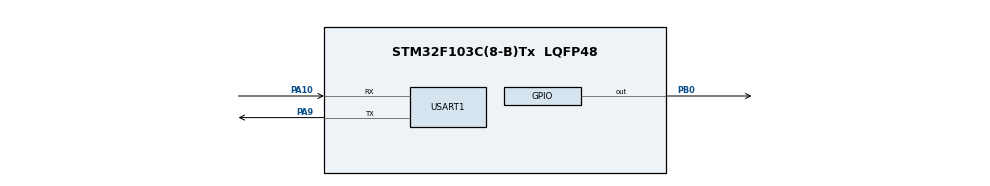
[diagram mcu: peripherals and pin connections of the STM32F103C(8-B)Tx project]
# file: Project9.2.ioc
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Mcu.Family=STM32F1
Mcu.Name=STM32F103C(8-B)Tx
Mcu.Package=LQFP48
NVIC.PriorityGroup=NVIC_PRIORITYGROUP_4
PA10.Mode=Asynchronous
PA10.Signal=USART1_RX
PA13.Mode=Serial_Wire
PA13.Signal=SYS_JTMS-SWDIO
PA14.Mode=Serial_Wire
PA14.Signal=SYS_JTCK-SWCLK
PA9.Mode=Asynchronous
PA9.Signal=USART1_TX
PB0.Signal=GPIO_Output
PD0-OSC_IN.Mode=HSE-External-Oscillator
PD0-OSC_IN.Signal=RCC_OSC_IN
PD1-OSC_OUT.Mode=HSE-External-Oscillator
PD1-OSC_OUT.Signal=RCC_OSC_OUT
ProjectManager.HeapSize=0x200
ProjectManager.StackSize=0x400
ProjectManager.TargetToolchain=MDK-ARM V5.32
RCC.AHBFreq_Value=72000000
RCC.APB1CLKDivider=RCC_HCLK_DIV2
RCC.APB1Freq_Value=36000000
RCC.APB1TimFreq_Value=72000000
RCC.APB2Freq_Value=72000000
RCC.APB2TimFreq_Value=72000000
RCC.HCLKFreq_Value=72000000
RCC.PLLMUL=RCC_PLL_MUL9
RCC.PLLSourceVirtual=RCC_PLLSOURCE_HSE
RCC.SYSCLKFreq_VALUE=72000000
RCC.SYSCLKSource=RCC_SYSCLKSOURCE_PLLCLK
RCC.USBFreq_Value=72000000
USART1.VirtualMode=VM_ASYNC
board=custom

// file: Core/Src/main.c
/* USER CODE BEGIN Header */
/**
  ******************************************************************************
  * @file           : main.c
  * @brief          : Main program body
  ******************************************************************************
  * @attention
  *
  * Copyright (c) 2026 STMicroelectronics.
  * All rights reserved.
  *
  * This software is licensed under terms that can be found in the LICENSE file
  * in the root directory of this software component.
  * If no LICENSE file comes with this software, it is provided AS-IS.
  *
  ******************************************************************************
  */
/* USER CODE END Header */
#include "main.h"

/* USER CODE BEGIN Includes */
#include <string.h>
/* USER CODE END Includes */

/* USER CODE BEGIN PD */
#define RX_BUF_SIZE 32
/* USER CODE END PD */

UART_HandleTypeDef huart1;

/* USER CODE BEGIN PV */
char rx_buf[RX_BUF_SIZE];
uint8_t rx_idx = 0;
uint8_t rx_char;
/* USER CODE END PV */

void SystemClock_Config(void);
static void MX_GPIO_Init(void);
static void MX_USART1_UART_Init(void);
/* USER CODE BEGIN PFP */
static void uart_print(const char *s);
static void process_command(char *cmd);
/* USER CODE END PFP */

int main(void)
{

  /* MCU Configuration--------------------------------------------------------*/

  /* Reset of all peripherals, Initializes the Flash interface and the Systick. */
  HAL_Init();

  /* Configure the system clock */
  SystemClock_Config();

  /* Initialize all configured peripherals */
  MX_GPIO_Init();
  MX_USART1_UART_Init();
  /* USER CODE BEGIN 2 */
  /* 3 blinks = firmware is running (PC13 is active-low) */
  for (int i = 0; i < 6; i++)
  {
    HAL_GPIO_TogglePin(GPIOC, GPIO_PIN_13);
    HAL_Delay(200);
  }
  HAL_GPIO_WritePin(GPIOC, GPIO_PIN_13, GPIO_PIN_SET); /* LED off */

  uart_print("\r\nSTM32 LED Command Interface\r\n");
  uart_print("Commands: LED ON | LED OFF | LED TOGGLE\r\n");
  uart_print("> ");
  /* USER CODE END 2 */

  /* Infinite loop */
  while (1)
  {

    /* USER CODE BEGIN 3 */
    if (HAL_UART_Receive(&huart1, &rx_char, 1, HAL_MAX_DELAY) == HAL_OK)
    {
      if (rx_char == '\r' || rx_char == '\n')      /* Enter pressed */
      {
        uart_print("\r\n");
        rx_buf[rx_idx] = '\0';
        process_command(rx_buf);
        rx_idx = 0;
        uart_print("> ");
      }
      else if (rx_char == 0x08 || rx_char == 0x7F) /* Backspace */
      {
        if (rx_idx > 0)
        {
          rx_idx--;
          uart_print("\b \b");
        }
      }
      else if (rx_idx < RX_BUF_SIZE - 1)
      {
        rx_buf[rx_idx++] = rx_char;
        HAL_UART_Transmit(&huart1, &rx_char, 1, HAL_MAX_DELAY); /* echo typed char */
      }
    }
  }
  /* USER CODE END 3 */
}

void SystemClock_Config(void)
{
  RCC_OscInitTypeDef RCC_OscInitStruct = {0};
  RCC_ClkInitTypeDef RCC_ClkInitStruct = {0};

  /* Internal oscillator (HSI/2 = 4 MHz) x 16 = 64 MHz. No external crystal needed. */
  RCC_OscInitStruct.OscillatorType = RCC_OSCILLATORTYPE_HSI;
  RCC_OscInitStruct.HSIState = RCC_HSI_ON;
  RCC_OscInitStruct.HSICalibrationValue = RCC_HSICALIBRATION_DEFAULT;
  RCC_OscInitStruct.PLL.PLLState = RCC_PLL_ON;
  RCC_OscInitStruct.PLL.PLLSource = RCC_PLLSOURCE_HSI_DIV2;
  RCC_OscInitStruct.PLL.PLLMUL = RCC_PLL_MUL16;
  if (HAL_RCC_OscConfig(&RCC_OscInitStruct) != HAL_OK)
  {
    Error_Handler();
  }

  RCC_ClkInitStruct.ClockType = RCC_CLOCKTYPE_HCLK|RCC_CLOCKTYPE_SYSCLK
                              |RCC_CLOCKTYPE_PCLK1|RCC_CLOCKTYPE_PCLK2;
  RCC_ClkInitStruct.SYSCLKSource = RCC_SYSCLKSOURCE_PLLCLK;
  RCC_ClkInitStruct.AHBCLKDivider = RCC_SYSCLK_DIV1;
  RCC_ClkInitStruct.APB1CLKDivider = RCC_HCLK_DIV2;
  RCC_ClkInitStruct.APB2CLKDivider = RCC_HCLK_DIV1;

  if (HAL_RCC_ClockConfig(&RCC_ClkInitStruct, FLASH_LATENCY_2) != HAL_OK)
  {
    Error_Handler();
  }
}

static void MX_USART1_UART_Init(void)
{

  huart1.Instance = USART1;
  huart1.Init.BaudRate = 115200;
  huart1.Init.WordLength = UART_WORDLENGTH_8B;
  huart1.Init.StopBits = UART_STOPBITS_1;
  huart1.Init.Parity = UART_PARITY_NONE;
  huart1.Init.Mode = UART_MODE_TX_RX;
  huart1.Init.HwFlowCtl = UART_HWCONTROL_NONE;
  huart1.Init.OverSampling = UART_OVERSAMPLING_16;
  if (HAL_UART_Init(&huart1) != HAL_OK)
  {
    Error_Handler();
  }

}

static void MX_GPIO_Init(void)
{
  GPIO_InitTypeDef GPIO_InitStruct = {0};

  /* GPIO Ports Clock Enable */
  __HAL_RCC_GPIOC_CLK_ENABLE();
  __HAL_RCC_GPIOD_CLK_ENABLE();
  __HAL_RCC_GPIOA_CLK_ENABLE();

  /*Configure GPIO pin Output Level (PC13 LED is active-low: SET = LED off) */
  HAL_GPIO_WritePin(GPIOC, GPIO_PIN_13, GPIO_PIN_SET);

  /*Configure GPIO pin : PC13 */
  GPIO_InitStruct.Pin = GPIO_PIN_13;
  GPIO_InitStruct.Mode = GPIO_MODE_OUTPUT_PP;
  GPIO_InitStruct.Pull = GPIO_NOPULL;
  GPIO_InitStruct.Speed = GPIO_SPEED_FREQ_LOW;
  HAL_GPIO_Init(GPIOC, &GPIO_InitStruct);

}

/* USER CODE BEGIN 4 */
static void uart_print(const char *s)
{
  HAL_UART_Transmit(&huart1, (uint8_t *)s, strlen(s), HAL_MAX_DELAY);
}

static void process_command(char *cmd)
{
  /* convert to uppercase so "led on" also works */
  for (uint8_t i = 0; cmd[i] != '\0'; i++)
  {
    if (cmd[i] >= 'a' && cmd[i] <= 'z')
      cmd[i] -= 32;
  }

  if (strcmp(cmd, "LED ON") == 0)
  {
    HAL_GPIO_WritePin(GPIOC, GPIO_PIN_13, GPIO_PIN_RESET); /* active-low: LOW = ON */
    uart_print("LED turned ON\r\n");
  }
  else if (strcmp(cmd, "LED OFF") == 0)
  {
    HAL_GPIO_WritePin(GPIOC, GPIO_PIN_13, GPIO_PIN_SET);   /* active-low: HIGH = OFF */
    uart_print("LED turned OFF\r\n");
  }
  else if (strcmp(cmd, "LED TOGGLE") == 0)
  {
    HAL_GPIO_TogglePin(GPIOC, GPIO_PIN_13);
    uart_print("LED toggled\r\n");
  }
  else if (cmd[0] != '\0')
  {
    uart_print("Unknown command\r\n");
  }
}
/* USER CODE END 4 */

void Error_Handler(void)
{
  __disable_irq();
  while (1)
  {
  }
}
